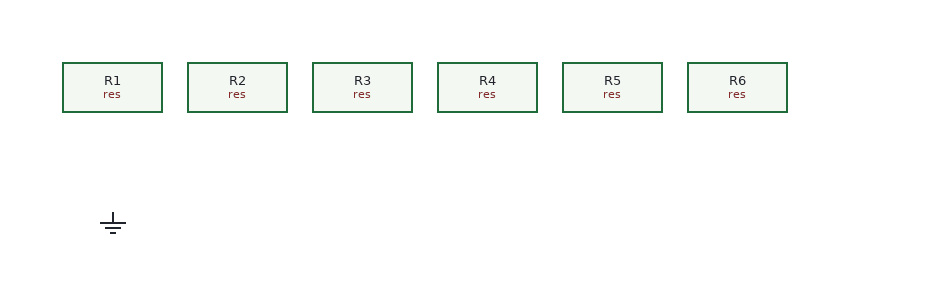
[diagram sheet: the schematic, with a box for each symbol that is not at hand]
v {xschem version=3.4.8RC file_version=1.3}
G {}
K {}
V {}
S {}
F {}
E {}
C {res.sym} 0 0 0 0 {name=R1 value="f00000001 f00000002 f00000003 f00000004 f00000005 f00000006 f00000007 f00000008 f00000009 f00000010 f00000011 f00000012 f00000013 f00000014 f00000015 f00000016 f00000017 f00000018" format="@name @pinlist @value"}
C {res.sym} 100 0 0 0 {name=R2 value="\{a01*b01\} \{a02*b02\} \{a03*b03\} \{a04*b04\} \{a05*b05\} \{a06*b06\} \{a07*b07\} \{a08*b08\} \{a09*b09\} \{a10*b10\} \{a11*b11\} \{a12*b12\} \{a13*b13\} \{a14*b14\} \{a15*b15\} \{a16*b16\} \{a17*b17\} \{a18*b18\}" format="@name @pinlist @value"}
C {res.sym} 200 0 0 0 {name=R3 value="/a/very/long/path/dddddddddddddddddddddddddddddddddddddddddddddddddddddddddddddddddddddddddddddddddddddddddddddddddddddddddddddddddddddddddddddddddddddddddddd/models.lib" format=".include @value"}
C {res.sym} 300 0 0 0 {name=R4 value="f00000001 f00000002 f00000003 f00000004 f00000005 f00000006 f00000007 f00000008 f00000009 f00000010 f00000011 f00000012 f00000013 f00000014 f00000015 f00000016 f00000017 f00000018" format="* comment @value"}
C {res.sym} 400 0 0 0 {name=R5 value="x'f00000001 f00000002 f00000003 f00000004 f00000005 f00000006 f00000007 f00000008 f00000009 f00000010 f00000011 f00000012 f00000013 f00000014 f00000015 f00000016 f00000017 f00000018" format="@name @pinlist @value"}
C {res.sym} 500 0 0 0 {name=R6 value="f00000001 f00000002 f00000003 f00000004 f00000005 f00000006 f00000007 f00000008 f00000009 f00000010 f00000011 f00000012 f00000013 f00000014 f00000015 f00000016 f00000017 f00000018" format="@name @pinlist @value"}
C {gnd.sym} 0 100 0 0 {name=l1 lab=0}
